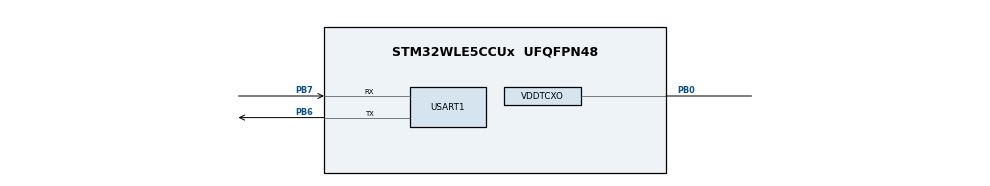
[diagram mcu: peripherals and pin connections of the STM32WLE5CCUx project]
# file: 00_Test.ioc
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FREERTOS.Tasks01=defaultTask,24,128,StartDefaultTask,Default,NULL,Dynamic,NULL,NULL
Mcu.Family=STM32WL
Mcu.Name=STM32WLE5CCUx
Mcu.Package=UFQFPN48
NVIC.PriorityGroup=NVIC_PRIORITYGROUP_4
NVIC.SUBGHZ_Radio_IRQn=true\:7\:0\:true\:false\:true\:true\:true\:true\:true
NVIC.TIM1_UP_IRQn=true\:15\:0\:false\:false\:true\:false\:false\:true\:true
NVIC.TimeBase=TIM1_UP_IRQn
NVIC.TimeBaseIP=TIM1
NVIC.USART1_IRQn=true\:5\:0\:true\:false\:true\:true\:true\:true\:true
OSC_IN.Mode=HSE-TCXO
OSC_IN.Signal=RCC_OSC_IN
PA13.Mode=Serial_Wire
PA13.Signal=DEBUG_JTMS-SWDIO
PA14.Mode=Serial_Wire
PA14.Signal=DEBUG_JTCK-SWCLK
PB0-VDD_TCXO.Mode=HSE-TCXO
PB0-VDD_TCXO.Signal=VDDTCXO
PB6.Mode=Asynchronous
PB6.Signal=USART1_TX
PB7.Mode=Asynchronous
PB7.Signal=USART1_RX
ProjectManager.HeapSize=0x200
ProjectManager.StackSize=0x400
ProjectManager.TargetToolchain=Makefile
RCC.AHBFreq_Value=32000000
RCC.APB1Freq_Value=32000000
RCC.APB1TimFreq_Value=32000000
RCC.APB2Freq_Value=32000000
RCC.APB2TimFreq_Value=32000000
RCC.APB3Freq_Value=32000000
RCC.CortexFreq_Value=32000000
RCC.HCLKFreq_Value=32000000
RCC.HSEPRES=2
RCC.HSE_VALUE=32000000
RCC.HSI_VALUE=16000000
RCC.LSE_VALUE=32768
RCC.PLLR=RCC_PLLR_DIV4
RCC.PLLSourceVirtual=RCC_PLLSOURCE_HSE
RCC.SYSCLKFreq_VALUE=32000000
RCC.SYSCLKSource=RCC_SYSCLKSOURCE_PLLCLK
RCC.VCOOutputFreq_Value=128000000
USART1.VirtualMode-Asynchronous=VM_ASYNC
VP_FREERTOS_VS_CMSIS_V2.Mode=CMSIS_V2
VP_SUBGHZ_VS_SUBGHZ.Mode=SUBGHZ_Activate
VP_SYS_VS_tim1.Mode=TIM1
board=custom

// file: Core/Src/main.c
/* USER CODE BEGIN Header */
/**
  ******************************************************************************
  * @file           : main.c
  * @brief          : Main program body
  ******************************************************************************
  * @attention
  *
  * Copyright (c) 2025 STMicroelectronics.
  * All rights reserved.
  *
  * This software is licensed under terms that can be found in the LICENSE file
  * in the root directory of this software component.
  * If no LICENSE file comes with this software, it is provided AS-IS.
  *
  ******************************************************************************
  */
/* USER CODE END Header */
#include "main.h"
#include "cmsis_os.h"
#include "subghz.h"
#include "usart.h"
#include "gpio.h"

void SystemClock_Config(void);
void MX_FREERTOS_Init(void);

int main(void)
{

  /* MCU Configuration--------------------------------------------------------*/

  /* Reset of all peripherals, Initializes the Flash interface and the Systick. */
  HAL_Init();

  /* Configure the system clock */
  SystemClock_Config();

  /* Initialize all configured peripherals */
  MX_GPIO_Init();
  MX_SUBGHZ_Init();
  MX_USART1_UART_Init();

  /* Init scheduler */
  osKernelInitialize();  /* Call init function for freertos objects (in cmsis_os2.c) */
  MX_FREERTOS_Init();

  /* Start scheduler */
  osKernelStart();

  /* We should never get here as control is now taken by the scheduler */

  /* Infinite loop */
  while (1)
  {

  }
}

void SystemClock_Config(void)
{
  RCC_OscInitTypeDef RCC_OscInitStruct = {0};
  RCC_ClkInitTypeDef RCC_ClkInitStruct = {0};

  /** Configure the main internal regulator output voltage
  */
  __HAL_PWR_VOLTAGESCALING_CONFIG(PWR_REGULATOR_VOLTAGE_SCALE1);

  /** Initializes the CPU, AHB and APB buses clocks
  */
  RCC_OscInitStruct.OscillatorType = RCC_OSCILLATORTYPE_HSE;
  RCC_OscInitStruct.HSEState = RCC_HSE_BYPASS_PWR;
  RCC_OscInitStruct.HSEDiv = RCC_HSE_DIV2;
  RCC_OscInitStruct.PLL.PLLState = RCC_PLL_ON;
  RCC_OscInitStruct.PLL.PLLSource = RCC_PLLSOURCE_HSE;
  RCC_OscInitStruct.PLL.PLLM = RCC_PLLM_DIV1;
  RCC_OscInitStruct.PLL.PLLN = 8;
  RCC_OscInitStruct.PLL.PLLP = RCC_PLLP_DIV2;
  RCC_OscInitStruct.PLL.PLLR = RCC_PLLR_DIV4;
  RCC_OscInitStruct.PLL.PLLQ = RCC_PLLQ_DIV2;
  if (HAL_RCC_OscConfig(&RCC_OscInitStruct) != HAL_OK)
  {
    Error_Handler();
  }

  /** Enable the HSE Prescaler
  */
  __HAL_RCC_HSE_DIV2_ENABLE();

  /** Configure the SYSCLKSource, HCLK, PCLK1 and PCLK2 clocks dividers
  */
  RCC_ClkInitStruct.ClockType = RCC_CLOCKTYPE_HCLK3|RCC_CLOCKTYPE_HCLK
                              |RCC_CLOCKTYPE_SYSCLK|RCC_CLOCKTYPE_PCLK1
                              |RCC_CLOCKTYPE_PCLK2;
  RCC_ClkInitStruct.SYSCLKSource = RCC_SYSCLKSOURCE_PLLCLK;
  RCC_ClkInitStruct.AHBCLKDivider = RCC_SYSCLK_DIV1;
  RCC_ClkInitStruct.APB1CLKDivider = RCC_HCLK_DIV1;
  RCC_ClkInitStruct.APB2CLKDivider = RCC_HCLK_DIV1;
  RCC_ClkInitStruct.AHBCLK3Divider = RCC_SYSCLK_DIV1;

  if (HAL_RCC_ClockConfig(&RCC_ClkInitStruct, FLASH_LATENCY_1) != HAL_OK)
  {
    Error_Handler();
  }
}

void HAL_TIM_PeriodElapsedCallback(TIM_HandleTypeDef *htim)
{
  if (htim->Instance == TIM1)
  {
    HAL_IncTick();
  }
}

void Error_Handler(void)
{
  __disable_irq();
  while (1)
  {
  }
}

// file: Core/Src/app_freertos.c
/* USER CODE BEGIN Header */
/**
  ******************************************************************************
  * File Name          : app_freertos.c
  * Description        : Code for freertos applications
  ******************************************************************************
  * @attention
  *
  * Copyright (c) 2025 STMicroelectronics.
  * All rights reserved.
  *
  * This software is licensed under terms that can be found in the LICENSE file
  * in the root directory of this software component.
  * If no LICENSE file comes with this software, it is provided AS-IS.
  *
  ******************************************************************************
  */
/* USER CODE END Header */

#include "FreeRTOS.h"
#include "task.h"
#include "main.h"
#include "cmsis_os.h"

/* Definitions for defaultTask */
osThreadId_t defaultTaskHandle;
const osThreadAttr_t defaultTask_attributes = {
  .name = "defaultTask",
  .priority = (osPriority_t) osPriorityNormal,
  .stack_size = 128 * 4
};

void StartDefaultTask(void *argument);

void MX_FREERTOS_Init(void); /* (MISRA C 2004 rule 8.1) */

void MX_FREERTOS_Init(void) {

  /* Create the thread(s) */
  /* creation of defaultTask */
  defaultTaskHandle = osThreadNew(StartDefaultTask, NULL, &defaultTask_attributes);

}

void StartDefaultTask(void *argument)
{
  for(;;)
  {
    osDelay(1);
  }
}
